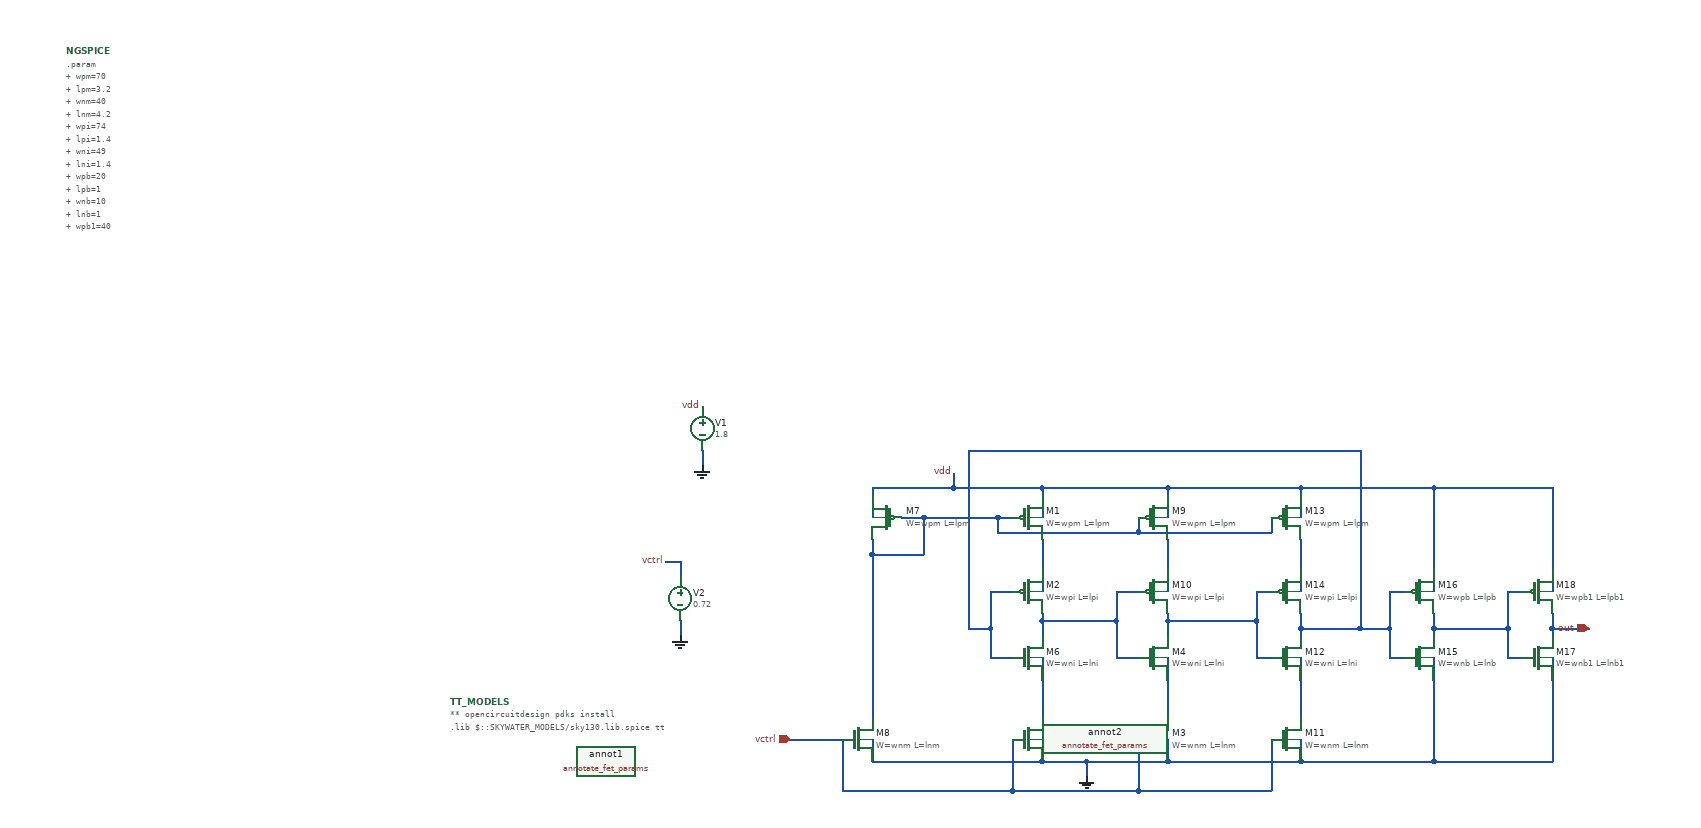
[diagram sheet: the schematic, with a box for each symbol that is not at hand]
v {xschem version=3.4.8RC file_version=1.3}
G {}
K {}
V {}
S {}
F {}
E {}
B 2 880 -740 1680 -340 {flags=graph
y1=-0.071
y2=1.9
ypos1=0
ypos2=2
divy=5
subdivy=1
unity=1
x1=6.8561632e-07
x2=1.3409763e-06
divx=5
subdivx=1
xlabmag=1.0
ylabmag=1.0
node=out
color=4
dataset=-1
unitx=1
logx=0
logy=0
hilight_wave=0}
N 590 -40 590 -20 {lab=#net1}
N 590 -150 590 -80 {lab=#net2}
N 520 -30 520 10 {lab=#net3}
N 520 -80 550 -80 {lab=#net3}
N 530 -180 550 -180 {lab=#net4}
N 360 -130 430 -130 {lab=#net4}
N 430 -180 430 -130 {lab=#net4}
N 550 120 550 190 {lab=vctrl}
N 320 120 320 190 {lab=vctrl}
N 250 120 320 120 {lab=vctrl}
N 360 120 360 150 {lab=0}
N 360 150 590 150 {lab=0}
N 590 120 590 150 {lab=0}
N 520 10 550 10 {lab=#net3}
N 360 -220 360 -180 {lab=vdd}
N 470 -220 590 -220 {lab=vdd}
N 590 -220 590 -180 {lab=vdd}
N 760 -150 760 -80 {lab=#net5}
N 720 120 720 190 {lab=vctrl}
N 760 120 760 150 {lab=0}
N 760 -220 760 -180 {lab=vdd}
N 590 -40 690 -40 {lab=#net1}
N 690 -80 690 -40 {lab=#net1}
N 690 -80 720 -80 {lab=#net1}
N 690 -40 690 10 {lab=#net1}
N 690 10 720 10 {lab=#net1}
N 590 -220 760 -220 {lab=vdd}
N 940 -150 940 -80 {lab=#net6}
N 900 120 900 190 {lab=vctrl}
N 940 120 940 150 {lab=0}
N 940 -220 940 -180 {lab=vdd}
N 760 -40 880 -40 {lab=#net7}
N 880 -80 880 -40 {lab=#net7}
N 880 -80 900 -80 {lab=#net7}
N 880 -40 880 10 {lab=#net7}
N 880 10 900 10 {lab=#net7}
N 1020 -30 1060 -30 {lab=#net3}
N 490 -270 490 -30 {lab=#net3}
N 490 -30 520 -30 {lab=#net3}
N 760 150 940 150 {lab=0}
N 720 190 900 190 {lab=vctrl}
N 360 -130 360 90 {lab=#net4}
N 650 150 650 170 {lab=0}
N 470 -240 470 -220 {lab=vdd}
N 760 -220 940 -220 {lab=vdd}
N 590 10 590 100 {lab=#net8}
N 130 -270 130 -250 {lab=0}
N 80 -120 100 -120 {lab=vctrl}
N 100 -120 100 -100 {lab=vctrl}
N 100 -40 100 -20 {lab=0}
N 530 -180 530 -160 {lab=#net4}
N 530 -160 720 -160 {lab=#net4}
N 720 -180 720 -160 {lab=#net4}
N 720 -160 900 -160 {lab=#net4}
N 900 -180 900 -160 {lab=#net4}
N 760 -40 760 -20 {lab=#net7}
N 760 10 760 100 {lab=#net9}
N 940 -30 940 -20 {lab=#net3}
N 940 10 940 100 {lab=#net10}
N 1020 -270 1020 -30 {lab=#net3}
N 1060 -80 1060 -30 {lab=#net3}
N 1060 -80 1080 -80 {lab=#net3}
N 1060 -30 1060 10 {lab=#net3}
N 1060 10 1080 10 {lab=#net3}
N 1120 -30 1120 -20 {lab=#net11}
N 1120 10 1120 150 {lab=0}
N 1120 -30 1220 -30 {lab=#net11}
N 1120 -220 1120 -80 {lab=vdd}
N 940 -220 1120 -220 {lab=vdd}
N 490 -270 1020 -270 {lab=#net3}
N 1220 -80 1220 -30 {lab=#net11}
N 1220 -80 1240 -80 {lab=#net11}
N 1220 -30 1220 10 {lab=#net11}
N 1220 10 1240 10 {lab=#net11}
N 1280 -30 1280 -20 {lab=out}
N 1280 10 1280 150 {lab=0}
N 1280 -30 1330 -30 {lab=out}
N 1120 -220 1280 -220 {lab=vdd}
N 1280 -220 1280 -80 {lab=vdd}
N 1120 150 1280 150 {lab=0}
N 360 -150 360 -130 {lab=#net4}
N 400 -180 430 -180 {lab=#net4}
N 320 190 550 190 {lab=vctrl}
N 360 -220 470 -220 {lab=vdd}
N 550 190 720 190 {lab=vctrl}
N 650 150 760 150 {lab=0}
N 590 -50 590 -40 {lab=#net1}
N 760 -50 760 -40 {lab=#net7}
N 940 -50 940 -30 {lab=#net3}
N 520 -80 520 -30 {lab=#net3}
N 590 150 650 150 {lab=0}
N 430 -180 530 -180 {lab=#net4}
N 940 -30 1020 -30 {lab=#net3}
N 1120 -50 1120 -30 {lab=#net11}
N 940 150 1120 150 {lab=0}
N 1280 -50 1280 -30 {lab=out}
C {sky130_fd_pr/pfet_01v8.sym} 380 -180 0 1 {name=M7
W="wpm"
L="lpm"
nf=1
mult=1
ad="expr('int((@nf + 1)/2) * @W / @nf * 0.29')"
pd="expr('2*int((@nf + 1)/2) * (@W / @nf + 0.29)')"
as="expr('int((@nf + 2)/2) * @W / @nf * 0.29')"
ps="expr('2*int((@nf + 2)/2) * (@W / @nf + 0.29)')"
nrd="expr('0.29 / @W ')" nrs="expr('0.29 / @W ')"
sa=0 sb=0 sd=0
model=pfet_01v8
spiceprefix=X
}
C {sky130_fd_pr/nfet_01v8.sym} 340 120 0 0 {name=M8
W="wnm"
L="lnm"
nf=1 
mult=1
ad="expr('int((@nf + 1)/2) * @W / @nf * 0.29')"
pd="expr('2*int((@nf + 1)/2) * (@W / @nf + 0.29)')"
as="expr('int((@nf + 2)/2) * @W / @nf * 0.29')"
ps="expr('2*int((@nf + 2)/2) * (@W / @nf + 0.29)')"
nrd="expr('0.29 / @W ')" nrs="expr('0.29 / @W ')"
sa=0 sb=0 sd=0
model=nfet_01v8
spiceprefix=X
}
C {sky130_fd_pr/nfet_01v8.sym} 570 120 0 0 {name=M5
W="wnm"
L="lnm"
nf=1 
mult=1
ad="expr('int((@nf + 1)/2) * @W / @nf * 0.29')"
pd="expr('2*int((@nf + 1)/2) * (@W / @nf + 0.29)')"
as="expr('int((@nf + 2)/2) * @W / @nf * 0.29')"
ps="expr('2*int((@nf + 2)/2) * (@W / @nf + 0.29)')"
nrd="expr('0.29 / @W ')" nrs="expr('0.29 / @W ')"
sa=0 sb=0 sd=0
model=nfet_01v8
spiceprefix=X
}
C {sky130_fd_pr/nfet_01v8.sym} 570 10 0 0 {name=M6
W="wni"
L="lni"
nf=1 
mult=1
ad="expr('int((@nf + 1)/2) * @W / @nf * 0.29')"
pd="expr('2*int((@nf + 1)/2) * (@W / @nf + 0.29)')"
as="expr('int((@nf + 2)/2) * @W / @nf * 0.29')"
ps="expr('2*int((@nf + 2)/2) * (@W / @nf + 0.29)')"
nrd="expr('0.29 / @W ')" nrs="expr('0.29 / @W ')"
sa=0 sb=0 sd=0
model=nfet_01v8
spiceprefix=X
}
C {sky130_fd_pr/pfet_01v8.sym} 570 -180 0 0 {name=M1
W="wpm"
L="lpm"
nf=1
mult=1
ad="expr('int((@nf + 1)/2) * @W / @nf * 0.29')"
pd="expr('2*int((@nf + 1)/2) * (@W / @nf + 0.29)')"
as="expr('int((@nf + 2)/2) * @W / @nf * 0.29')"
ps="expr('2*int((@nf + 2)/2) * (@W / @nf + 0.29)')"
nrd="expr('0.29 / @W ')" nrs="expr('0.29 / @W ')"
sa=0 sb=0 sd=0
model=pfet_01v8
spiceprefix=X
}
C {sky130_fd_pr/pfet_01v8.sym} 570 -80 0 0 {name=M2
W="wpi"
L="lpi"
nf=1
mult=1
ad="expr('int((@nf + 1)/2) * @W / @nf * 0.29')"
pd="expr('2*int((@nf + 1)/2) * (@W / @nf + 0.29)')"
as="expr('int((@nf + 2)/2) * @W / @nf * 0.29')"
ps="expr('2*int((@nf + 2)/2) * (@W / @nf + 0.29)')"
nrd="expr('0.29 / @W ')" nrs="expr('0.29 / @W ')"
sa=0 sb=0 sd=0
model=pfet_01v8
spiceprefix=X
}
C {sky130_fd_pr/nfet_01v8.sym} 740 120 0 0 {name=M3
W="wnm"
L="lnm"
nf=1 
mult=1
ad="expr('int((@nf + 1)/2) * @W / @nf * 0.29')"
pd="expr('2*int((@nf + 1)/2) * (@W / @nf + 0.29)')"
as="expr('int((@nf + 2)/2) * @W / @nf * 0.29')"
ps="expr('2*int((@nf + 2)/2) * (@W / @nf + 0.29)')"
nrd="expr('0.29 / @W ')" nrs="expr('0.29 / @W ')"
sa=0 sb=0 sd=0
model=nfet_01v8
spiceprefix=X
}
C {sky130_fd_pr/pfet_01v8.sym} 740 -180 0 0 {name=M9
W="wpm"
L="lpm"
nf=1
mult=1
ad="expr('int((@nf + 1)/2) * @W / @nf * 0.29')"
pd="expr('2*int((@nf + 1)/2) * (@W / @nf + 0.29)')"
as="expr('int((@nf + 2)/2) * @W / @nf * 0.29')"
ps="expr('2*int((@nf + 2)/2) * (@W / @nf + 0.29)')"
nrd="expr('0.29 / @W ')" nrs="expr('0.29 / @W ')"
sa=0 sb=0 sd=0
model=pfet_01v8
spiceprefix=X
}
C {sky130_fd_pr/nfet_01v8.sym} 920 120 0 0 {name=M11
W="wnm"
L="lnm"
nf=1 
mult=1
ad="expr('int((@nf + 1)/2) * @W / @nf * 0.29')"
pd="expr('2*int((@nf + 1)/2) * (@W / @nf + 0.29)')"
as="expr('int((@nf + 2)/2) * @W / @nf * 0.29')"
ps="expr('2*int((@nf + 2)/2) * (@W / @nf + 0.29)')"
nrd="expr('0.29 / @W ')" nrs="expr('0.29 / @W ')"
sa=0 sb=0 sd=0
model=nfet_01v8
spiceprefix=X
}
C {sky130_fd_pr/pfet_01v8.sym} 920 -180 0 0 {name=M13
W="wpm"
L="lpm"
nf=1
mult=1
ad="expr('int((@nf + 1)/2) * @W / @nf * 0.29')"
pd="expr('2*int((@nf + 1)/2) * (@W / @nf + 0.29)')"
as="expr('int((@nf + 2)/2) * @W / @nf * 0.29')"
ps="expr('2*int((@nf + 2)/2) * (@W / @nf + 0.29)')"
nrd="expr('0.29 / @W ')" nrs="expr('0.29 / @W ')"
sa=0 sb=0 sd=0
model=pfet_01v8
spiceprefix=X
}
C {ipin.sym} 250 120 0 0 {name=p1 lab=vctrl}
C {iopin.sym} 1330 -30 0 0 {name=p2 lab=out}
C {code_shown.sym} -730 -810 0 0 {name=NGSPICE only_toplevel=false value="
.param
+ wpm=70
+ lpm=3.2
+ wnm=40
+ lnm=4.2
+ wpi=74
+ lpi=1.4
+ wni=49
+ lni=1.4
+ wpb=20
+ lpb=1
+ wnb=10
+ lnb=1
+ wpb1=40
+ lpb1=1
+ wnb1=20
+ lnb1=1

.control
    tran 1n 2u
    write vco_tb.raw
   meas tran t_period trig v(out) val=0.9 rise=2 targ v(out) val=0.9 rise=3
  let freq = 1/t_period
  print freq
.endc
"}
C {gnd.sym} 650 170 0 0 {name=l2 lab=0}
C {vsource.sym} 130 -300 0 0 {name=V1 value=1.8 savecurrent=false}
C {lab_pin.sym} 130 -330 0 0 {name=p4 sig_type=std_logic lab=vdd}
C {gnd.sym} 130 -250 0 0 {name=l3 lab=0}
C {vsource.sym} 100 -70 0 0 {name=V2 value=0.72 savecurrent=false}
C {gnd.sym} 100 -20 0 0 {name=l4 lab=0}
C {sky130_fd_pr/nfet_01v8.sym} 740 10 0 0 {name=M4
W="wni"
L="lni"
nf=1 
mult=1
ad="expr('int((@nf + 1)/2) * @W / @nf * 0.29')"
pd="expr('2*int((@nf + 1)/2) * (@W / @nf + 0.29)')"
as="expr('int((@nf + 2)/2) * @W / @nf * 0.29')"
ps="expr('2*int((@nf + 2)/2) * (@W / @nf + 0.29)')"
nrd="expr('0.29 / @W ')" nrs="expr('0.29 / @W ')"
sa=0 sb=0 sd=0
model=nfet_01v8
spiceprefix=X
}
C {sky130_fd_pr/pfet_01v8.sym} 740 -80 0 0 {name=M10
W="wpi"
L="lpi"
nf=1
mult=1
ad="expr('int((@nf + 1)/2) * @W / @nf * 0.29')"
pd="expr('2*int((@nf + 1)/2) * (@W / @nf + 0.29)')"
as="expr('int((@nf + 2)/2) * @W / @nf * 0.29')"
ps="expr('2*int((@nf + 2)/2) * (@W / @nf + 0.29)')"
nrd="expr('0.29 / @W ')" nrs="expr('0.29 / @W ')"
sa=0 sb=0 sd=0
model=pfet_01v8
spiceprefix=X
}
C {sky130_fd_pr/nfet_01v8.sym} 920 10 0 0 {name=M12
W="wni"
L="lni"
nf=1 
mult=1
ad="expr('int((@nf + 1)/2) * @W / @nf * 0.29')"
pd="expr('2*int((@nf + 1)/2) * (@W / @nf + 0.29)')"
as="expr('int((@nf + 2)/2) * @W / @nf * 0.29')"
ps="expr('2*int((@nf + 2)/2) * (@W / @nf + 0.29)')"
nrd="expr('0.29 / @W ')" nrs="expr('0.29 / @W ')"
sa=0 sb=0 sd=0
model=nfet_01v8
spiceprefix=X
}
C {sky130_fd_pr/pfet_01v8.sym} 920 -80 0 0 {name=M14
W="wpi"
L="lpi"
nf=1
mult=1
ad="expr('int((@nf + 1)/2) * @W / @nf * 0.29')"
pd="expr('2*int((@nf + 1)/2) * (@W / @nf + 0.29)')"
as="expr('int((@nf + 2)/2) * @W / @nf * 0.29')"
ps="expr('2*int((@nf + 2)/2) * (@W / @nf + 0.29)')"
nrd="expr('0.29 / @W ')" nrs="expr('0.29 / @W ')"
sa=0 sb=0 sd=0
model=pfet_01v8
spiceprefix=X
}
C {lab_pin.sym} 80 -120 0 0 {name=p5 sig_type=std_logic lab=vctrl}
C {lab_pin.sym} 470 -240 0 0 {name=p3 sig_type=std_logic lab=vdd}
C {devices/code.sym} -210 70 0 0 {name=TT_MODELS
only_toplevel=true
format="tcleval( @value )"
value="
** opencircuitdesign pdks install
.lib $::SKYWATER_MODELS/sky130.lib.spice tt
"
spice_ignore=false}
C {sky130_fd_pr/annotate_fet_params.sym} 0 150 0 0 {name=annot1 ref=M7}
C {sky130_fd_pr/annotate_fet_params.sym} 90 150 0 0 {name=annot2 ref=M8}
C {sky130_fd_pr/nfet_01v8.sym} 1100 10 0 0 {name=M15
W="wnb"
L="lnb"
nf=1 
mult=1
ad="expr('int((@nf + 1)/2) * @W / @nf * 0.29')"
pd="expr('2*int((@nf + 1)/2) * (@W / @nf + 0.29)')"
as="expr('int((@nf + 2)/2) * @W / @nf * 0.29')"
ps="expr('2*int((@nf + 2)/2) * (@W / @nf + 0.29)')"
nrd="expr('0.29 / @W ')" nrs="expr('0.29 / @W ')"
sa=0 sb=0 sd=0
model=nfet_01v8
spiceprefix=X
}
C {sky130_fd_pr/pfet_01v8.sym} 1100 -80 0 0 {name=M16
W="wpb"
L="lpb"
nf=1
mult=1
ad="expr('int((@nf + 1)/2) * @W / @nf * 0.29')"
pd="expr('2*int((@nf + 1)/2) * (@W / @nf + 0.29)')"
as="expr('int((@nf + 2)/2) * @W / @nf * 0.29')"
ps="expr('2*int((@nf + 2)/2) * (@W / @nf + 0.29)')"
nrd="expr('0.29 / @W ')" nrs="expr('0.29 / @W ')"
sa=0 sb=0 sd=0
model=pfet_01v8
spiceprefix=X
}
C {sky130_fd_pr/nfet_01v8.sym} 1260 10 0 0 {name=M17
W="wnb1"
L="lnb1"
nf=1 
mult=1
ad="expr('int((@nf + 1)/2) * @W / @nf * 0.29')"
pd="expr('2*int((@nf + 1)/2) * (@W / @nf + 0.29)')"
as="expr('int((@nf + 2)/2) * @W / @nf * 0.29')"
ps="expr('2*int((@nf + 2)/2) * (@W / @nf + 0.29)')"
nrd="expr('0.29 / @W ')" nrs="expr('0.29 / @W ')"
sa=0 sb=0 sd=0
model=nfet_01v8
spiceprefix=X
}
C {sky130_fd_pr/pfet_01v8.sym} 1260 -80 0 0 {name=M18
W="wpb1"
L="lpb1"
nf=1
mult=1
ad="expr('int((@nf + 1)/2) * @W / @nf * 0.29')"
pd="expr('2*int((@nf + 1)/2) * (@W / @nf + 0.29)')"
as="expr('int((@nf + 2)/2) * @W / @nf * 0.29')"
ps="expr('2*int((@nf + 2)/2) * (@W / @nf + 0.29)')"
nrd="expr('0.29 / @W ')" nrs="expr('0.29 / @W ')"
sa=0 sb=0 sd=0
model=pfet_01v8
spiceprefix=X
}
C {launcher.sym} 670 -430 0 0 {name=h5
descr="load waves"
tclcommand="xschem raw_read $netlist_dir/vco_tb.raw tran"
}
